VERSION 5.8 ;
BUSBITCHARS "[]" ;
DIVIDERCHAR "/" ;
UNITS
    DATABASE MICRONS 1000 ;
END UNITS
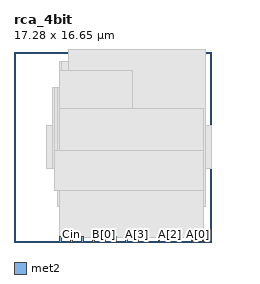
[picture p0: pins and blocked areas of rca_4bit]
MACRO rca_4bit
  FOREIGN rca_4bit 0 0 ;
  CLASS BLOCK ;
  SIZE 17.28 BY 16.65 ;
  PIN A[0]
    DIRECTION INPUT ;
    USE SIGNAL ;
    PORT
      LAYER met2 ;
        RECT  16.49 0 16.63 0.485 ;
    END
  END A[0]
  PIN A[1]
    DIRECTION INPUT ;
    USE SIGNAL ;
    PORT
      LAYER met2 ;
        RECT  9.77 0 9.91 0.485 ;
    END
  END A[1]
  PIN A[2]
    DIRECTION INPUT ;
    USE SIGNAL ;
    PORT
      LAYER met2 ;
        RECT  13.61 0 13.75 0.485 ;
    END
  END A[2]
  PIN A[3]
    DIRECTION INPUT ;
    USE SIGNAL ;
    PORT
      LAYER met2 ;
        RECT  10.73 0 10.87 0.485 ;
    END
  END A[3]
  PIN B[0]
    DIRECTION INPUT ;
    USE SIGNAL ;
    PORT
      LAYER met2 ;
        RECT  7.85 0 7.99 0.485 ;
    END
  END B[0]
  PIN B[1]
    DIRECTION INPUT ;
    USE SIGNAL ;
    PORT
      LAYER met2 ;
        RECT  6.89 0 7.03 0.485 ;
    END
  END B[1]
  PIN B[2]
    DIRECTION INPUT ;
    USE SIGNAL ;
    PORT
      LAYER met2 ;
        RECT  15.53 0 15.67 0.485 ;
    END
  END B[2]
  PIN B[3]
    DIRECTION INPUT ;
    USE SIGNAL ;
    PORT
      LAYER met2 ;
        RECT  11.69 0 11.83 0.485 ;
    END
  END B[3]
  PIN Cin
    DIRECTION INPUT ;
    USE SIGNAL ;
    PORT
      LAYER met2 ;
        RECT  4.97 0 5.11 0.485 ;
    END
  END Cin
  PIN S[0]
    DIRECTION OUTPUT ;
    USE SIGNAL ;
    PORT
      LAYER met2 ;
        RECT  14.57 0 14.71 0.485 ;
    END
  END S[0]
  PIN S[1]
    DIRECTION OUTPUT ;
    USE SIGNAL ;
    PORT
      LAYER met2 ;
        RECT  4.01 0 4.15 0.485 ;
    END
  END S[1]
  PIN S[2]
    DIRECTION OUTPUT ;
    USE SIGNAL ;
    PORT
      LAYER met2 ;
        RECT  12.65 0 12.79 0.485 ;
    END
  END S[2]
  PIN Cout
    DIRECTION OUTPUT ;
    USE SIGNAL ;
    PORT
      LAYER met2 ;
        RECT  5.93 0 6.07 0.485 ;
    END
  END Cout
  PIN S[3]
    DIRECTION OUTPUT ;
    USE SIGNAL ;
    PORT
      LAYER met2 ;
        RECT  8.81 0 8.95 0.485 ;
    END
  END S[3]
  OBS
    LAYER li1 ;
     RECT  3.84 3.245 16.8 6.575 ;
     RECT  2.88 6.575 17.28 10.075 ;
     RECT  3.36 10.075 16.8 13.405 ;
     RECT  4.8 13.405 16.8 16.735 ;
    LAYER met1 ;
     RECT  2.88 6.415 3.36 10.235 ;
     RECT  3.36 6.415 3.53 13.565 ;
     RECT  3.53 4.555 3.84 13.565 ;
     RECT  3.84 3.085 4.01 13.565 ;
     RECT  4.01 3.085 4.8 15.795 ;
     RECT  4.8 3.085 16.8 16.895 ;
     RECT  16.8 6.415 17.28 10.235 ;
    LAYER met2 ;
     RECT  4.01 0.37 16.63 4.555 ;
     RECT  3.53 4.555 16.63 8.025 ;
     RECT  4.01 8.025 16.63 11.725 ;
     RECT  4.01 11.725 10.39 15.055 ;
     RECT  4.01 15.055 4.15 15.795 ;
  END
END rca_4bit
END LIBRARY
